###############################################################
#  Generated by:      Cadence Innovus 21.14-s109_1
#  OS:                Linux x86_64(Host ID caen-vnc-mi17.engin.umich.edu)
#  Generated on:      Wed Apr 19 02:55:07 2023
#  Design:            Main_controller
#  Command:           write_lef_abstract /afs/umich.edu/class/eecs627/w23/groups/group4/CNN_LSTM/Main_controller_new/apr/Main_controller/data/Main_controller.lef -specifyTopLayer 4 -stripePin -PGpinLayers 4
###############################################################

VERSION 5.8 ;

BUSBITCHARS "[]" ;
DIVIDERCHAR "/" ;

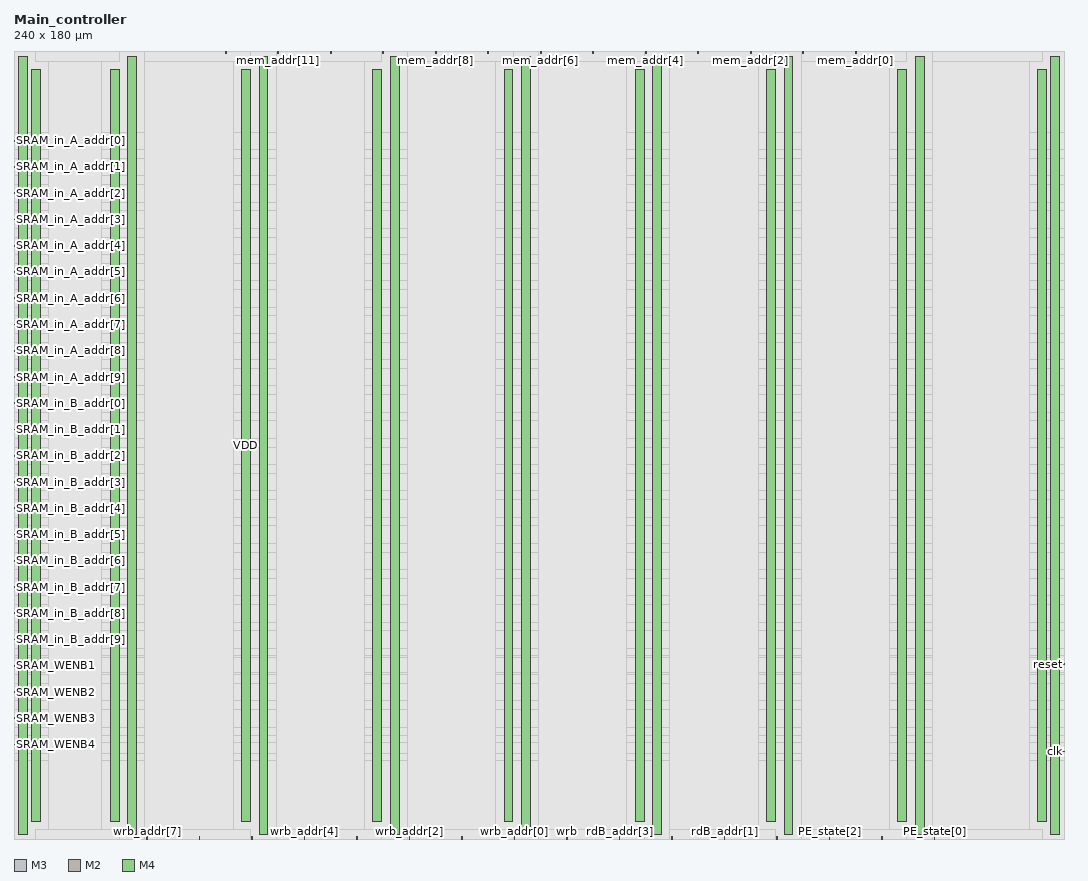
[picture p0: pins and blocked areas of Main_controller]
MACRO Main_controller
  CLASS BLOCK ;
  SIZE 240.000000 BY 180.000000 ;
  FOREIGN Main_controller 0.000000 0.000000 ;
  ORIGIN 0 0 ;
  SYMMETRY X Y R90 ;
  PIN clk
    DIRECTION INPUT ;
    USE SIGNAL ;
    ANTENNAPARTIALMETALAREA 4.3 LAYER M3  ;
    ANTENNAPARTIALMETALSIDEAREA 0.043 LAYER M3  ;
    ANTENNAPARTIALCUTAREA 0.08 LAYER V3  ;
    ANTENNAPARTIALMETALAREA 2.2 LAYER M4  ;
    ANTENNAPARTIALMETALSIDEAREA 0.0224 LAYER M4  ;
    ANTENNAMODEL OXIDE1 ;
    ANTENNAGATEAREA 0.8352 LAYER M4  ;
    ANTENNAMAXAREACAR 3.58046 LAYER M4  ;
    ANTENNAMAXSIDEAREACAR 0.0370929 LAYER M4  ;
    ANTENNAMAXCUTCAR 0.287356 LAYER V4  ;
    PORT
      LAYER M3 ;
        RECT 239.400000 19.900000 240.000000 20.100000 ;
    END
  END clk
  PIN reset
    DIRECTION INPUT ;
    USE SIGNAL ;
    ANTENNAPARTIALMETALAREA 30.9 LAYER M3  ;
    ANTENNAPARTIALMETALSIDEAREA 0.3102 LAYER M3  ;
    ANTENNAMODEL OXIDE1 ;
    ANTENNAGATEAREA 1.1424 LAYER M3  ;
    ANTENNAMAXAREACAR 32.7996 LAYER M3  ;
    ANTENNAMAXSIDEAREACAR 0.329482 LAYER M3  ;
    ANTENNAPARTIALCUTAREA 0.08 LAYER V3  ;
    ANTENNAMAXCUTCAR 1.60849 LAYER V3  ;
    ANTENNAPARTIALMETALAREA 2.44 LAYER M4  ;
    ANTENNAPARTIALMETALSIDEAREA 0.0248 LAYER M4  ;
    ANTENNAGATEAREA 1.2984 LAYER M4  ;
    ANTENNAMAXAREACAR 34.6788 LAYER M4  ;
    ANTENNAMAXSIDEAREACAR 0.348583 LAYER M4  ;
    ANTENNAMAXCUTCAR 1.60849 LAYER V4  ;
    PORT
      LAYER M3 ;
        RECT 239.400000 39.900000 240.000000 40.100000 ;
    END
  END reset
  PIN wrb
    DIRECTION OUTPUT ;
    USE SIGNAL ;
    ANTENNAPARTIALMETALAREA 2.46 LAYER M2  ;
    ANTENNAPARTIALMETALSIDEAREA 0.0246 LAYER M2  ;
    ANTENNAPARTIALCUTAREA 0.08 LAYER V2  ;
    ANTENNADIFFAREA 2.014 LAYER M3  ;
    ANTENNAPARTIALMETALAREA 7.08 LAYER M3  ;
    ANTENNAPARTIALMETALSIDEAREA 0.0712 LAYER M3  ;
    ANTENNAMODEL OXIDE1 ;
    ANTENNAGATEAREA 0.1728 LAYER M3  ;
    ANTENNAMAXAREACAR 81.6696 LAYER M3  ;
    ANTENNAMAXSIDEAREACAR 0.819792 LAYER M3  ;
    ANTENNAMAXCUTCAR 0.925926 LAYER V3  ;
    PORT
      LAYER M2 ;
        RECT 126.300000 0.000000 126.500000 0.600000 ;
    END
  END wrb
  PIN PE_state[2]
    DIRECTION OUTPUT ;
    USE SIGNAL ;
    ANTENNAPARTIALMETALAREA 10.3 LAYER M2  ;
    ANTENNAPARTIALMETALSIDEAREA 0.103 LAYER M2  ;
    ANTENNAPARTIALCUTAREA 0.08 LAYER V2  ;
    ANTENNADIFFAREA 1.792 LAYER M3  ;
    ANTENNAPARTIALMETALAREA 17.08 LAYER M3  ;
    ANTENNAPARTIALMETALSIDEAREA 0.1712 LAYER M3  ;
    PORT
      LAYER M2 ;
        RECT 186.300000 0.000000 186.500000 0.600000 ;
    END
  END PE_state[2]
  PIN PE_state[1]
    DIRECTION OUTPUT ;
    USE SIGNAL ;
    ANTENNAPARTIALMETALAREA 6.7 LAYER M2  ;
    ANTENNAPARTIALMETALSIDEAREA 0.067 LAYER M2  ;
    ANTENNAPARTIALCUTAREA 0.08 LAYER V2  ;
    ANTENNADIFFAREA 1.76 LAYER M3  ;
    ANTENNAPARTIALMETALAREA 14.84 LAYER M3  ;
    ANTENNAPARTIALMETALSIDEAREA 0.1488 LAYER M3  ;
    PORT
      LAYER M2 ;
        RECT 198.300000 0.000000 198.500000 0.600000 ;
    END
  END PE_state[1]
  PIN PE_state[0]
    DIRECTION OUTPUT ;
    USE SIGNAL ;
    ANTENNAPARTIALMETALAREA 9.58 LAYER M2  ;
    ANTENNAPARTIALMETALSIDEAREA 0.0958 LAYER M2  ;
    ANTENNAPARTIALCUTAREA 0.08 LAYER V2  ;
    ANTENNADIFFAREA 1.16 LAYER M3  ;
    ANTENNAPARTIALMETALAREA 17.88 LAYER M3  ;
    ANTENNAPARTIALMETALSIDEAREA 0.1792 LAYER M3  ;
    PORT
      LAYER M2 ;
        RECT 210.300000 0.000000 210.500000 0.600000 ;
    END
  END PE_state[0]
  PIN wrb_addr[7]
    DIRECTION OUTPUT ;
    USE SIGNAL ;
    ANTENNAPARTIALMETALAREA 2.3 LAYER M2  ;
    ANTENNAPARTIALMETALSIDEAREA 0.023 LAYER M2  ;
    ANTENNAPARTIALCUTAREA 0.08 LAYER V2  ;
    ANTENNADIFFAREA 2.014 LAYER M3  ;
    ANTENNAPARTIALMETALAREA 3.96 LAYER M3  ;
    ANTENNAPARTIALMETALSIDEAREA 0.04 LAYER M3  ;
    ANTENNAMODEL OXIDE1 ;
    ANTENNAGATEAREA 0.2808 LAYER M3  ;
    ANTENNAMAXAREACAR 16.9238 LAYER M3  ;
    ANTENNAMAXSIDEAREACAR 0.174117 LAYER M3  ;
    ANTENNAMAXCUTCAR 0.909091 LAYER V3  ;
    PORT
      LAYER M2 ;
        RECT 30.300000 0.000000 30.500000 0.600000 ;
    END
  END wrb_addr[7]
  PIN wrb_addr[6]
    DIRECTION OUTPUT ;
    USE SIGNAL ;
    ANTENNAPARTIALMETALAREA 4.72 LAYER M2  ;
    ANTENNAPARTIALMETALSIDEAREA 0.0472 LAYER M2  ;
    ANTENNAMODEL OXIDE1 ;
    ANTENNAGATEAREA 0.1488 LAYER M2  ;
    ANTENNAMAXAREACAR 33.7184 LAYER M2  ;
    ANTENNAMAXSIDEAREACAR 0.336156 LAYER M2  ;
    ANTENNAPARTIALCUTAREA 0.24 LAYER V2  ;
    ANTENNAMAXCUTCAR 2.15054 LAYER V2  ;
    ANTENNADIFFAREA 2.014 LAYER M3  ;
    ANTENNAPARTIALMETALAREA 4.12 LAYER M3  ;
    ANTENNAPARTIALMETALSIDEAREA 0.0424 LAYER M3  ;
    ANTENNAGATEAREA 0.5688 LAYER M3  ;
    ANTENNAMAXAREACAR 40.9617 LAYER M3  ;
    ANTENNAMAXSIDEAREACAR 0.410699 LAYER M3  ;
    ANTENNAMAXCUTCAR 2.15054 LAYER V3  ;
    PORT
      LAYER M2 ;
        RECT 42.300000 0.000000 42.500000 0.600000 ;
    END
  END wrb_addr[6]
  PIN wrb_addr[5]
    DIRECTION OUTPUT ;
    USE SIGNAL ;
    ANTENNAPARTIALMETALAREA 1.26 LAYER M2  ;
    ANTENNAPARTIALMETALSIDEAREA 0.0126 LAYER M2  ;
    ANTENNAPARTIALCUTAREA 0.08 LAYER V2  ;
    ANTENNADIFFAREA 2.014 LAYER M3  ;
    ANTENNAPARTIALMETALAREA 3.08 LAYER M3  ;
    ANTENNAPARTIALMETALSIDEAREA 0.032 LAYER M3  ;
    ANTENNAMODEL OXIDE1 ;
    ANTENNAGATEAREA 0.528 LAYER M3  ;
    ANTENNAMAXAREACAR 27.5531 LAYER M3  ;
    ANTENNAMAXSIDEAREACAR 0.281036 LAYER M3  ;
    ANTENNAMAXCUTCAR 1.34409 LAYER V3  ;
    PORT
      LAYER M2 ;
        RECT 54.300000 0.000000 54.500000 0.600000 ;
    END
  END wrb_addr[5]
  PIN wrb_addr[4]
    DIRECTION OUTPUT ;
    USE SIGNAL ;
    ANTENNAPARTIALMETALAREA 1.58 LAYER M2  ;
    ANTENNAPARTIALMETALSIDEAREA 0.0158 LAYER M2  ;
    ANTENNAPARTIALCUTAREA 0.08 LAYER V2  ;
    ANTENNADIFFAREA 2.014 LAYER M3  ;
    ANTENNAPARTIALMETALAREA 2.92 LAYER M3  ;
    ANTENNAPARTIALMETALSIDEAREA 0.0304 LAYER M3  ;
    ANTENNAMODEL OXIDE1 ;
    ANTENNAGATEAREA 0.6912 LAYER M3  ;
    ANTENNAMAXAREACAR 7.92454 LAYER M3  ;
    ANTENNAMAXSIDEAREACAR 0.0814174 LAYER M3  ;
    ANTENNAMAXCUTCAR 1.07527 LAYER V3  ;
    PORT
      LAYER M2 ;
        RECT 66.300000 0.000000 66.500000 0.600000 ;
    END
  END wrb_addr[4]
  PIN wrb_addr[3]
    DIRECTION OUTPUT ;
    USE SIGNAL ;
    ANTENNAPARTIALMETALAREA 1.26 LAYER M2  ;
    ANTENNAPARTIALMETALSIDEAREA 0.0126 LAYER M2  ;
    ANTENNAPARTIALCUTAREA 0.08 LAYER V2  ;
    ANTENNADIFFAREA 2.014 LAYER M3  ;
    ANTENNAPARTIALMETALAREA 1.68 LAYER M3  ;
    ANTENNAPARTIALMETALSIDEAREA 0.0176 LAYER M3  ;
    ANTENNAMODEL OXIDE1 ;
    ANTENNAGATEAREA 0.264 LAYER M3  ;
    ANTENNAMAXAREACAR 14.4409 LAYER M3  ;
    ANTENNAMAXSIDEAREACAR 0.146364 LAYER M3  ;
    ANTENNAMAXCUTCAR 0.909091 LAYER V3  ;
    PORT
      LAYER M2 ;
        RECT 78.300000 0.000000 78.500000 0.600000 ;
    END
  END wrb_addr[3]
  PIN wrb_addr[2]
    DIRECTION OUTPUT ;
    USE SIGNAL ;
    ANTENNAPARTIALMETALAREA 1.5 LAYER M2  ;
    ANTENNAPARTIALMETALSIDEAREA 0.015 LAYER M2  ;
    ANTENNAPARTIALCUTAREA 0.08 LAYER V2  ;
    ANTENNADIFFAREA 2.014 LAYER M3  ;
    ANTENNAPARTIALMETALAREA 2.4 LAYER M3  ;
    ANTENNAPARTIALMETALSIDEAREA 0.0248 LAYER M3  ;
    ANTENNAMODEL OXIDE1 ;
    ANTENNAGATEAREA 0.696 LAYER M3  ;
    ANTENNAMAXAREACAR 10.1235 LAYER M3  ;
    ANTENNAMAXSIDEAREACAR 0.101162 LAYER M3  ;
    ANTENNAMAXCUTCAR 0.786164 LAYER V3  ;
    PORT
      LAYER M2 ;
        RECT 90.300000 0.000000 90.500000 0.600000 ;
    END
  END wrb_addr[2]
  PIN wrb_addr[1]
    DIRECTION OUTPUT ;
    USE SIGNAL ;
    ANTENNAPARTIALMETALAREA 1.82 LAYER M2  ;
    ANTENNAPARTIALMETALSIDEAREA 0.0182 LAYER M2  ;
    ANTENNAPARTIALCUTAREA 0.08 LAYER V2  ;
    ANTENNADIFFAREA 2.014 LAYER M3  ;
    ANTENNAPARTIALMETALAREA 5.4 LAYER M3  ;
    ANTENNAPARTIALMETALSIDEAREA 0.0552 LAYER M3  ;
    ANTENNAMODEL OXIDE1 ;
    ANTENNAGATEAREA 0.66 LAYER M3  ;
    ANTENNAMAXAREACAR 13.5468 LAYER M3  ;
    ANTENNAMAXSIDEAREACAR 0.144185 LAYER M3  ;
    ANTENNAMAXCUTCAR 1.78571 LAYER V3  ;
    PORT
      LAYER M2 ;
        RECT 102.300000 0.000000 102.500000 0.600000 ;
    END
  END wrb_addr[1]
  PIN wrb_addr[0]
    DIRECTION OUTPUT ;
    USE SIGNAL ;
    ANTENNAPARTIALMETALAREA 1.82 LAYER M2  ;
    ANTENNAPARTIALMETALSIDEAREA 0.0182 LAYER M2  ;
    ANTENNAPARTIALCUTAREA 0.08 LAYER V2  ;
    ANTENNADIFFAREA 2.014 LAYER M3  ;
    ANTENNAPARTIALMETALAREA 9.8 LAYER M3  ;
    ANTENNAPARTIALMETALSIDEAREA 0.0992 LAYER M3  ;
    ANTENNAMODEL OXIDE1 ;
    ANTENNAGATEAREA 0.4968 LAYER M3  ;
    ANTENNAMAXAREACAR 30.1171 LAYER M3  ;
    ANTENNAMAXSIDEAREACAR 0.312322 LAYER M3  ;
    ANTENNAMAXCUTCAR 1.72414 LAYER V3  ;
    PORT
      LAYER M2 ;
        RECT 114.300000 0.000000 114.500000 0.600000 ;
    END
  END wrb_addr[0]
  PIN rdB_addr[3]
    DIRECTION OUTPUT ;
    USE SIGNAL ;
    ANTENNAPARTIALMETALAREA 3.9 LAYER M2  ;
    ANTENNAPARTIALMETALSIDEAREA 0.039 LAYER M2  ;
    ANTENNAPARTIALCUTAREA 0.08 LAYER V2  ;
    ANTENNADIFFAREA 2.624 LAYER M3  ;
    ANTENNAPARTIALMETALAREA 7.56 LAYER M3  ;
    ANTENNAPARTIALMETALSIDEAREA 0.076 LAYER M3  ;
    PORT
      LAYER M2 ;
        RECT 138.300000 0.000000 138.500000 0.600000 ;
    END
  END rdB_addr[3]
  PIN rdB_addr[2]
    DIRECTION OUTPUT ;
    USE SIGNAL ;
    ANTENNAPARTIALMETALAREA 5.02 LAYER M2  ;
    ANTENNAPARTIALMETALSIDEAREA 0.0502 LAYER M2  ;
    ANTENNAPARTIALCUTAREA 0.08 LAYER V2  ;
    ANTENNADIFFAREA 7.362 LAYER M3  ;
    ANTENNAPARTIALMETALAREA 7.36 LAYER M3  ;
    ANTENNAPARTIALMETALSIDEAREA 0.0744 LAYER M3  ;
    ANTENNAMODEL OXIDE1 ;
    ANTENNAGATEAREA 0.156 LAYER M3  ;
    ANTENNAMAXAREACAR 61.7128 LAYER M3  ;
    ANTENNAMAXSIDEAREACAR 0.625385 LAYER M3  ;
    ANTENNAMAXCUTCAR 0.769231 LAYER V3  ;
    PORT
      LAYER M2 ;
        RECT 150.300000 0.000000 150.500000 0.600000 ;
    END
  END rdB_addr[2]
  PIN rdB_addr[1]
    DIRECTION OUTPUT ;
    USE SIGNAL ;
    ANTENNAPARTIALMETALAREA 8.62 LAYER M2  ;
    ANTENNAPARTIALMETALSIDEAREA 0.0862 LAYER M2  ;
    ANTENNAPARTIALCUTAREA 0.08 LAYER V2  ;
    ANTENNAPARTIALMETALAREA 9.08 LAYER M3  ;
    ANTENNAPARTIALMETALSIDEAREA 0.0912 LAYER M3  ;
    ANTENNAMODEL OXIDE1 ;
    ANTENNAGATEAREA 0.2952 LAYER M3  ;
    ANTENNAMAXAREACAR 32.3686 LAYER M3  ;
    ANTENNAMAXSIDEAREACAR 0.3271 LAYER M3  ;
    ANTENNAPARTIALCUTAREA 0.08 LAYER V3  ;
    ANTENNAMAXCUTCAR 0.677507 LAYER V3  ;
    ANTENNADIFFAREA 7.396 LAYER M4  ;
    ANTENNAPARTIALMETALAREA 3.88 LAYER M4  ;
    ANTENNAPARTIALMETALSIDEAREA 0.0392 LAYER M4  ;
    ANTENNAGATEAREA 0.468 LAYER M4  ;
    ANTENNAMAXAREACAR 40.6592 LAYER M4  ;
    ANTENNAMAXSIDEAREACAR 0.410861 LAYER M4  ;
    ANTENNAMAXCUTCAR 1.15741 LAYER V4  ;
    PORT
      LAYER M2 ;
        RECT 162.300000 0.000000 162.500000 0.600000 ;
    END
  END rdB_addr[1]
  PIN rdB_addr[0]
    DIRECTION OUTPUT ;
    USE SIGNAL ;
    ANTENNAPARTIALMETALAREA 8.94 LAYER M2  ;
    ANTENNAPARTIALMETALSIDEAREA 0.0894 LAYER M2  ;
    ANTENNAPARTIALCUTAREA 0.08 LAYER V2  ;
    ANTENNADIFFAREA 3.348 LAYER M3  ;
    ANTENNAPARTIALMETALAREA 12.08 LAYER M3  ;
    ANTENNAPARTIALMETALSIDEAREA 0.1216 LAYER M3  ;
    ANTENNAMODEL OXIDE1 ;
    ANTENNAGATEAREA 0.624 LAYER M3  ;
    ANTENNAMAXAREACAR 32.1275 LAYER M3  ;
    ANTENNAMAXSIDEAREACAR 0.320335 LAYER M3  ;
    ANTENNAMAXCUTCAR 0.925926 LAYER V3  ;
    PORT
      LAYER M2 ;
        RECT 174.300000 0.000000 174.500000 0.600000 ;
    END
  END rdB_addr[0]
  PIN mem_addr[12]
    DIRECTION OUTPUT ;
    USE SIGNAL ;
    ANTENNAPARTIALMETALAREA 1.5944 LAYER M2  ;
    ANTENNAPARTIALMETALSIDEAREA 0.01596 LAYER M2  ;
    ANTENNAPARTIALCUTAREA 0.08 LAYER V2  ;
    ANTENNADIFFAREA 2.014 LAYER M3  ;
    ANTENNAPARTIALMETALAREA 2.4 LAYER M3  ;
    ANTENNAPARTIALMETALSIDEAREA 0.0248 LAYER M3  ;
    ANTENNAMODEL OXIDE1 ;
    ANTENNAGATEAREA 0.2904 LAYER M3  ;
    ANTENNAMAXAREACAR 29.2675 LAYER M3  ;
    ANTENNAMAXSIDEAREACAR 0.298884 LAYER M3  ;
    ANTENNAMAXCUTCAR 1.51515 LAYER V3  ;
    PORT
      LAYER M2 ;
        RECT 48.320000 179.440000 48.480000 180.000000 ;
    END
  END mem_addr[12]
  PIN mem_addr[11]
    DIRECTION OUTPUT ;
    USE SIGNAL ;
    ANTENNAPARTIALMETALAREA 1.7544 LAYER M2  ;
    ANTENNAPARTIALMETALSIDEAREA 0.01756 LAYER M2  ;
    ANTENNAPARTIALCUTAREA 0.08 LAYER V2  ;
    ANTENNADIFFAREA 2.014 LAYER M3  ;
    ANTENNAPARTIALMETALAREA 0.84 LAYER M3  ;
    ANTENNAPARTIALMETALSIDEAREA 0.0088 LAYER M3  ;
    ANTENNAMODEL OXIDE1 ;
    ANTENNAGATEAREA 0.372 LAYER M3  ;
    ANTENNAMAXAREACAR 11.4153 LAYER M3  ;
    ANTENNAMAXSIDEAREACAR 0.118732 LAYER M3  ;
    ANTENNAMAXCUTCAR 0.757576 LAYER V3  ;
    PORT
      LAYER M2 ;
        RECT 60.320000 179.440000 60.480000 180.000000 ;
    END
  END mem_addr[11]
  PIN mem_addr[10]
    DIRECTION OUTPUT ;
    USE SIGNAL ;
    ANTENNAPARTIALMETALAREA 2.164 LAYER M2  ;
    ANTENNAPARTIALMETALSIDEAREA 0.02164 LAYER M2  ;
    ANTENNAMODEL OXIDE1 ;
    ANTENNAGATEAREA 0.1176 LAYER M2  ;
    ANTENNAMAXAREACAR 19.8707 LAYER M2  ;
    ANTENNAMAXSIDEAREACAR 0.20034 LAYER M2  ;
    ANTENNAPARTIALCUTAREA 0.08 LAYER V2  ;
    ANTENNAMAXCUTCAR 1.02041 LAYER V2  ;
    ANTENNADIFFAREA 2.014 LAYER M3  ;
    ANTENNAPARTIALMETALAREA 1.24 LAYER M3  ;
    ANTENNAPARTIALMETALSIDEAREA 0.0128 LAYER M3  ;
    ANTENNAGATEAREA 0.4896 LAYER M3  ;
    ANTENNAMAXAREACAR 22.4034 LAYER M3  ;
    ANTENNAMAXSIDEAREACAR 0.226484 LAYER M3  ;
    ANTENNAMAXCUTCAR 1.02041 LAYER V3  ;
    PORT
      LAYER M2 ;
        RECT 72.320000 179.440000 72.480000 180.000000 ;
    END
  END mem_addr[10]
  PIN mem_addr[9]
    DIRECTION OUTPUT ;
    USE SIGNAL ;
    ANTENNAPARTIALMETALAREA 1.4344 LAYER M2  ;
    ANTENNAPARTIALMETALSIDEAREA 0.01436 LAYER M2  ;
    ANTENNAPARTIALCUTAREA 0.08 LAYER V2  ;
    ANTENNADIFFAREA 2.014 LAYER M3  ;
    ANTENNAPARTIALMETALAREA 1.28 LAYER M3  ;
    ANTENNAPARTIALMETALSIDEAREA 0.0136 LAYER M3  ;
    ANTENNAMODEL OXIDE1 ;
    ANTENNAGATEAREA 0.408 LAYER M3  ;
    ANTENNAMAXAREACAR 16.2988 LAYER M3  ;
    ANTENNAMAXSIDEAREACAR 0.165492 LAYER M3  ;
    ANTENNAMAXCUTCAR 1.16657 LAYER V3  ;
    PORT
      LAYER M2 ;
        RECT 84.320000 179.440000 84.480000 180.000000 ;
    END
  END mem_addr[9]
  PIN mem_addr[8]
    DIRECTION OUTPUT ;
    USE SIGNAL ;
    ANTENNAPARTIALMETALAREA 1.9944 LAYER M2  ;
    ANTENNAPARTIALMETALSIDEAREA 0.01996 LAYER M2  ;
    ANTENNAPARTIALCUTAREA 0.08 LAYER V2  ;
    ANTENNADIFFAREA 2.014 LAYER M3  ;
    ANTENNAPARTIALMETALAREA 1.24 LAYER M3  ;
    ANTENNAPARTIALMETALSIDEAREA 0.0128 LAYER M3  ;
    ANTENNAMODEL OXIDE1 ;
    ANTENNAGATEAREA 0.4896 LAYER M3  ;
    ANTENNAMAXAREACAR 10.8861 LAYER M3  ;
    ANTENNAMAXSIDEAREACAR 0.112519 LAYER M3  ;
    ANTENNAMAXCUTCAR 0.757576 LAYER V3  ;
    PORT
      LAYER M2 ;
        RECT 96.320000 179.440000 96.480000 180.000000 ;
    END
  END mem_addr[8]
  PIN mem_addr[7]
    DIRECTION OUTPUT ;
    USE SIGNAL ;
    ANTENNAPARTIALMETALAREA 1.9144 LAYER M2  ;
    ANTENNAPARTIALMETALSIDEAREA 0.01916 LAYER M2  ;
    ANTENNAPARTIALCUTAREA 0.08 LAYER V2  ;
    ANTENNADIFFAREA 2.014 LAYER M3  ;
    ANTENNAPARTIALMETALAREA 3.4 LAYER M3  ;
    ANTENNAPARTIALMETALSIDEAREA 0.0344 LAYER M3  ;
    ANTENNAMODEL OXIDE1 ;
    ANTENNAGATEAREA 0.4896 LAYER M3  ;
    ANTENNAMAXAREACAR 11.5562 LAYER M3  ;
    ANTENNAMAXSIDEAREACAR 0.119883 LAYER M3  ;
    ANTENNAMAXCUTCAR 1.02041 LAYER V3  ;
    PORT
      LAYER M2 ;
        RECT 108.320000 179.440000 108.480000 180.000000 ;
    END
  END mem_addr[7]
  PIN mem_addr[6]
    DIRECTION OUTPUT ;
    USE SIGNAL ;
    ANTENNAPARTIALMETALAREA 1.9944 LAYER M2  ;
    ANTENNAPARTIALMETALSIDEAREA 0.01996 LAYER M2  ;
    ANTENNAMODEL OXIDE1 ;
    ANTENNAGATEAREA 0.1536 LAYER M2  ;
    ANTENNAMAXAREACAR 14.3034 LAYER M2  ;
    ANTENNAMAXSIDEAREACAR 0.14388 LAYER M2  ;
    ANTENNAPARTIALCUTAREA 0.08 LAYER V2  ;
    ANTENNAMAXCUTCAR 0.78125 LAYER V2  ;
    ANTENNADIFFAREA 2.014 LAYER M3  ;
    ANTENNAPARTIALMETALAREA 3.04 LAYER M3  ;
    ANTENNAPARTIALMETALSIDEAREA 0.0312 LAYER M3  ;
    ANTENNAGATEAREA 0.516 LAYER M3  ;
    ANTENNAMAXAREACAR 20.1949 LAYER M3  ;
    ANTENNAMAXSIDEAREACAR 0.204345 LAYER M3  ;
    ANTENNAMAXCUTCAR 1.6129 LAYER V3  ;
    PORT
      LAYER M2 ;
        RECT 120.320000 179.440000 120.480000 180.000000 ;
    END
  END mem_addr[6]
  PIN mem_addr[5]
    DIRECTION OUTPUT ;
    USE SIGNAL ;
    ANTENNADIFFAREA 2.014 LAYER M2  ;
    ANTENNAPARTIALMETALAREA 4.0744 LAYER M2  ;
    ANTENNAPARTIALMETALSIDEAREA 0.04076 LAYER M2  ;
    ANTENNAPARTIALCUTAREA 0.08 LAYER V2  ;
    ANTENNADIFFAREA 2.014 LAYER M3  ;
    ANTENNAPARTIALMETALAREA 0.84 LAYER M3  ;
    ANTENNAPARTIALMETALSIDEAREA 0.0088 LAYER M3  ;
    ANTENNAMODEL OXIDE1 ;
    ANTENNAGATEAREA 0.4896 LAYER M3  ;
    ANTENNAMAXAREACAR 5.47976 LAYER M3  ;
    ANTENNAMAXSIDEAREACAR 0.058455 LAYER M3  ;
    ANTENNAMAXCUTCAR 0.757576 LAYER V3  ;
    PORT
      LAYER M2 ;
        RECT 132.320000 179.440000 132.480000 180.000000 ;
    END
  END mem_addr[5]
  PIN mem_addr[4]
    DIRECTION OUTPUT ;
    USE SIGNAL ;
    ANTENNAPARTIALMETALAREA 1.9144 LAYER M2  ;
    ANTENNAPARTIALMETALSIDEAREA 0.01916 LAYER M2  ;
    ANTENNAPARTIALCUTAREA 0.08 LAYER V2  ;
    ANTENNADIFFAREA 2.014 LAYER M3  ;
    ANTENNAPARTIALMETALAREA 3.76 LAYER M3  ;
    ANTENNAPARTIALMETALSIDEAREA 0.0384 LAYER M3  ;
    ANTENNAMODEL OXIDE1 ;
    ANTENNAGATEAREA 0.4896 LAYER M3  ;
    ANTENNAMAXAREACAR 11.3436 LAYER M3  ;
    ANTENNAMAXSIDEAREACAR 0.118225 LAYER M3  ;
    ANTENNAMAXCUTCAR 1.02041 LAYER V3  ;
    PORT
      LAYER M2 ;
        RECT 144.320000 179.440000 144.480000 180.000000 ;
    END
  END mem_addr[4]
  PIN mem_addr[3]
    DIRECTION OUTPUT ;
    USE SIGNAL ;
    ANTENNAPARTIALMETALAREA 1.9144 LAYER M2  ;
    ANTENNAPARTIALMETALSIDEAREA 0.01916 LAYER M2  ;
    ANTENNAPARTIALCUTAREA 0.08 LAYER V2  ;
    ANTENNADIFFAREA 2.014 LAYER M3  ;
    ANTENNAPARTIALMETALAREA 4.72 LAYER M3  ;
    ANTENNAPARTIALMETALSIDEAREA 0.048 LAYER M3  ;
    ANTENNAMODEL OXIDE1 ;
    ANTENNAGATEAREA 0.4776 LAYER M3  ;
    ANTENNAMAXAREACAR 24.0781 LAYER M3  ;
    ANTENNAMAXSIDEAREACAR 0.244027 LAYER M3  ;
    ANTENNAMAXCUTCAR 1.59387 LAYER V3  ;
    PORT
      LAYER M2 ;
        RECT 156.320000 179.440000 156.480000 180.000000 ;
    END
  END mem_addr[3]
  PIN mem_addr[2]
    DIRECTION OUTPUT ;
    USE SIGNAL ;
    ANTENNAPARTIALMETALAREA 2.3144 LAYER M2  ;
    ANTENNAPARTIALMETALSIDEAREA 0.02316 LAYER M2  ;
    ANTENNAPARTIALCUTAREA 0.08 LAYER V2  ;
    ANTENNADIFFAREA 2.014 LAYER M3  ;
    ANTENNAPARTIALMETALAREA 5 LAYER M3  ;
    ANTENNAPARTIALMETALSIDEAREA 0.0504 LAYER M3  ;
    ANTENNAMODEL OXIDE1 ;
    ANTENNAGATEAREA 0.372 LAYER M3  ;
    ANTENNAMAXAREACAR 15.5274 LAYER M3  ;
    ANTENNAMAXSIDEAREACAR 0.159853 LAYER M3  ;
    ANTENNAPARTIALCUTAREA 0.08 LAYER V3  ;
    ANTENNAMAXCUTCAR 0.97263 LAYER V3  ;
    ANTENNADIFFAREA 2.014 LAYER M4  ;
    ANTENNAPARTIALMETALAREA 0.6 LAYER M4  ;
    ANTENNAPARTIALMETALSIDEAREA 0.0064 LAYER M4  ;
    ANTENNAGATEAREA 0.4896 LAYER M4  ;
    ANTENNAMAXAREACAR 16.7528 LAYER M4  ;
    ANTENNAMAXSIDEAREACAR 0.172924 LAYER M4  ;
    ANTENNAMAXCUTCAR 1.70068 LAYER V4  ;
    PORT
      LAYER M2 ;
        RECT 168.320000 179.440000 168.480000 180.000000 ;
    END
  END mem_addr[2]
  PIN mem_addr[1]
    DIRECTION OUTPUT ;
    USE SIGNAL ;
    ANTENNAPARTIALMETALAREA 3.5144 LAYER M2  ;
    ANTENNAPARTIALMETALSIDEAREA 0.03516 LAYER M2  ;
    ANTENNAPARTIALCUTAREA 0.08 LAYER V2  ;
    ANTENNADIFFAREA 2.014 LAYER M3  ;
    ANTENNAPARTIALMETALAREA 3.96 LAYER M3  ;
    ANTENNAPARTIALMETALSIDEAREA 0.04 LAYER M3  ;
    ANTENNAMODEL OXIDE1 ;
    ANTENNAGATEAREA 0.2976 LAYER M3  ;
    ANTENNAMAXAREACAR 22.4445 LAYER M3  ;
    ANTENNAMAXSIDEAREACAR 0.235221 LAYER M3  ;
    ANTENNAMAXCUTCAR 1.41824 LAYER V3  ;
    PORT
      LAYER M2 ;
        RECT 180.320000 179.440000 180.480000 180.000000 ;
    END
  END mem_addr[1]
  PIN mem_addr[0]
    DIRECTION OUTPUT ;
    USE SIGNAL ;
    ANTENNAPARTIALMETALAREA 3.0344 LAYER M2  ;
    ANTENNAPARTIALMETALSIDEAREA 0.03036 LAYER M2  ;
    ANTENNAPARTIALCUTAREA 0.08 LAYER V2  ;
    ANTENNADIFFAREA 2.014 LAYER M3  ;
    ANTENNAPARTIALMETALAREA 6.28 LAYER M3  ;
    ANTENNAPARTIALMETALSIDEAREA 0.0632 LAYER M3  ;
    ANTENNAMODEL OXIDE1 ;
    ANTENNAGATEAREA 0.3048 LAYER M3  ;
    ANTENNAMAXAREACAR 23.7103 LAYER M3  ;
    ANTENNAMAXSIDEAREACAR 0.241249 LAYER M3  ;
    ANTENNAMAXCUTCAR 0.540245 LAYER V3  ;
    PORT
      LAYER M2 ;
        RECT 192.320000 179.440000 192.480000 180.000000 ;
    END
  END mem_addr[0]
  PIN SRAM_in_A_addr[9]
    DIRECTION OUTPUT ;
    USE SIGNAL ;
    ANTENNAPARTIALMETALAREA 11.1544 LAYER M3  ;
    ANTENNAPARTIALMETALSIDEAREA 0.11196 LAYER M3  ;
    ANTENNAPARTIALCUTAREA 0.08 LAYER V3  ;
    ANTENNADIFFAREA 2.176 LAYER M4  ;
    ANTENNAPARTIALMETALAREA 4.68 LAYER M4  ;
    ANTENNAPARTIALMETALSIDEAREA 0.0472 LAYER M4  ;
    ANTENNAMODEL OXIDE1 ;
    ANTENNAGATEAREA 0.7344 LAYER M4  ;
    ANTENNAMAXAREACAR 27.4867 LAYER M4  ;
    ANTENNAMAXSIDEAREACAR 0.277922 LAYER M4  ;
    ANTENNAMAXCUTCAR 1.24534 LAYER V4  ;
    PORT
      LAYER M3 ;
        RECT 0.000000 105.520000 0.560000 105.680000 ;
    END
  END SRAM_in_A_addr[9]
  PIN SRAM_in_A_addr[8]
    DIRECTION OUTPUT ;
    USE SIGNAL ;
    ANTENNAPARTIALMETALAREA 5.9144 LAYER M3  ;
    ANTENNAPARTIALMETALSIDEAREA 0.05916 LAYER M3  ;
    ANTENNAPARTIALCUTAREA 0.08 LAYER V3  ;
    ANTENNADIFFAREA 4.168 LAYER M4  ;
    ANTENNAPARTIALMETALAREA 6.08 LAYER M4  ;
    ANTENNAPARTIALMETALSIDEAREA 0.0616 LAYER M4  ;
    ANTENNAMODEL OXIDE1 ;
    ANTENNAGATEAREA 1.1496 LAYER M4  ;
    ANTENNAMAXAREACAR 20.409 LAYER M4  ;
    ANTENNAMAXSIDEAREACAR 0.213352 LAYER M4  ;
    ANTENNAMAXCUTCAR 1.07576 LAYER V4  ;
    PORT
      LAYER M3 ;
        RECT 0.000000 111.520000 0.560000 111.680000 ;
    END
  END SRAM_in_A_addr[8]
  PIN SRAM_in_A_addr[7]
    DIRECTION OUTPUT ;
    USE SIGNAL ;
    ANTENNADIFFAREA 4.168 LAYER M3  ;
    ANTENNAPARTIALMETALAREA 16.804 LAYER M3  ;
    ANTENNAPARTIALMETALSIDEAREA 0.16964 LAYER M3  ;
    ANTENNAMODEL OXIDE1 ;
    ANTENNAGATEAREA 0.9312 LAYER M3  ;
    ANTENNAMAXAREACAR 33.0733 LAYER M3  ;
    ANTENNAMAXSIDEAREACAR 0.344674 LAYER M3  ;
    ANTENNAPARTIALCUTAREA 0.08 LAYER V3  ;
    ANTENNAMAXCUTCAR 2.16924 LAYER V3  ;
    ANTENNADIFFAREA 4.168 LAYER M4  ;
    ANTENNAPARTIALMETALAREA 2.36 LAYER M4  ;
    ANTENNAPARTIALMETALSIDEAREA 0.024 LAYER M4  ;
    ANTENNAGATEAREA 1.0896 LAYER M4  ;
    ANTENNAMAXAREACAR 35.2392 LAYER M4  ;
    ANTENNAMAXSIDEAREACAR 0.3667 LAYER M4  ;
    ANTENNAMAXCUTCAR 2.16924 LAYER V4  ;
    PORT
      LAYER M3 ;
        RECT 0.000000 117.520000 0.560000 117.680000 ;
    END
  END SRAM_in_A_addr[7]
  PIN SRAM_in_A_addr[6]
    DIRECTION OUTPUT ;
    USE SIGNAL ;
    ANTENNADIFFAREA 4.168 LAYER M3  ;
    ANTENNAPARTIALMETALAREA 20.6344 LAYER M3  ;
    ANTENNAPARTIALMETALSIDEAREA 0.20876 LAYER M3  ;
    ANTENNAMODEL OXIDE1 ;
    ANTENNAGATEAREA 3.2544 LAYER M3  ;
    ANTENNAMAXAREACAR 51.8503 LAYER M3  ;
    ANTENNAMAXSIDEAREACAR 0.523461 LAYER M3  ;
    ANTENNAMAXCUTCAR 1.6129 LAYER V3  ;
    PORT
      LAYER M3 ;
        RECT 0.000000 123.520000 0.560000 123.680000 ;
    END
  END SRAM_in_A_addr[6]
  PIN SRAM_in_A_addr[5]
    DIRECTION OUTPUT ;
    USE SIGNAL ;
    ANTENNAPARTIALMETALAREA 9.9144 LAYER M3  ;
    ANTENNAPARTIALMETALSIDEAREA 0.09996 LAYER M3  ;
    ANTENNAMODEL OXIDE1 ;
    ANTENNAGATEAREA 0.444 LAYER M3  ;
    ANTENNAMAXAREACAR 36.3831 LAYER M3  ;
    ANTENNAMAXSIDEAREACAR 0.365455 LAYER M3  ;
    ANTENNAPARTIALCUTAREA 0.08 LAYER V3  ;
    ANTENNAMAXCUTCAR 1.25545 LAYER V3  ;
    ANTENNADIFFAREA 3.996 LAYER M4  ;
    ANTENNAPARTIALMETALAREA 9.16 LAYER M4  ;
    ANTENNAPARTIALMETALSIDEAREA 0.0928 LAYER M4  ;
    ANTENNAGATEAREA 2.532 LAYER M4  ;
    ANTENNAMAXAREACAR 40.0007 LAYER M4  ;
    ANTENNAMAXSIDEAREACAR 0.402106 LAYER M4  ;
    ANTENNAMAXCUTCAR 1.77175 LAYER V4  ;
    PORT
      LAYER M3 ;
        RECT 0.000000 129.520000 0.560000 129.680000 ;
    END
  END SRAM_in_A_addr[5]
  PIN SRAM_in_A_addr[4]
    DIRECTION OUTPUT ;
    USE SIGNAL ;
    ANTENNADIFFAREA 2.014 LAYER M3  ;
    ANTENNAPARTIALMETALAREA 12.5144 LAYER M3  ;
    ANTENNAPARTIALMETALSIDEAREA 0.12556 LAYER M3  ;
    ANTENNAMODEL OXIDE1 ;
    ANTENNAGATEAREA 0.372 LAYER M3  ;
    ANTENNAMAXAREACAR 46.8385 LAYER M3  ;
    ANTENNAMAXSIDEAREACAR 0.473007 LAYER M3  ;
    ANTENNAMAXCUTCAR 0.757576 LAYER V3  ;
    PORT
      LAYER M3 ;
        RECT 0.000000 135.520000 0.560000 135.680000 ;
    END
  END SRAM_in_A_addr[4]
  PIN SRAM_in_A_addr[3]
    DIRECTION OUTPUT ;
    USE SIGNAL ;
    ANTENNADIFFAREA 4.168 LAYER M3  ;
    ANTENNAPARTIALMETALAREA 13.7944 LAYER M3  ;
    ANTENNAPARTIALMETALSIDEAREA 0.13916 LAYER M3  ;
    ANTENNAMODEL OXIDE1 ;
    ANTENNAGATEAREA 1.2768 LAYER M3  ;
    ANTENNAMAXAREACAR 41.9073 LAYER M3  ;
    ANTENNAMAXSIDEAREACAR 0.426924 LAYER M3  ;
    ANTENNAMAXCUTCAR 1.47679 LAYER V3  ;
    PORT
      LAYER M3 ;
        RECT 0.000000 141.520000 0.560000 141.680000 ;
    END
  END SRAM_in_A_addr[3]
  PIN SRAM_in_A_addr[2]
    DIRECTION OUTPUT ;
    USE SIGNAL ;
    ANTENNADIFFAREA 4.168 LAYER M3  ;
    ANTENNAPARTIALMETALAREA 13.4744 LAYER M3  ;
    ANTENNAPARTIALMETALSIDEAREA 0.13596 LAYER M3  ;
    ANTENNAMODEL OXIDE1 ;
    ANTENNAGATEAREA 0.792 LAYER M3  ;
    ANTENNAMAXAREACAR 20.6759 LAYER M3  ;
    ANTENNAMAXSIDEAREACAR 0.211641 LAYER M3  ;
    ANTENNAPARTIALCUTAREA 0.16 LAYER V3  ;
    ANTENNAMAXCUTCAR 1.5041 LAYER V3  ;
    ANTENNADIFFAREA 4.168 LAYER M4  ;
    ANTENNAPARTIALMETALAREA 12.84 LAYER M4  ;
    ANTENNAPARTIALMETALSIDEAREA 0.1296 LAYER M4  ;
    ANTENNAGATEAREA 1.4832 LAYER M4  ;
    ANTENNAMAXAREACAR 29.3328 LAYER M4  ;
    ANTENNAMAXSIDEAREACAR 0.299019 LAYER M4  ;
    ANTENNAMAXCUTCAR 2.87356 LAYER V4  ;
    PORT
      LAYER M3 ;
        RECT 0.000000 147.520000 0.560000 147.680000 ;
    END
  END SRAM_in_A_addr[2]
  PIN SRAM_in_A_addr[1]
    DIRECTION OUTPUT ;
    USE SIGNAL ;
    ANTENNADIFFAREA 4.168 LAYER M3  ;
    ANTENNAPARTIALMETALAREA 15.5544 LAYER M3  ;
    ANTENNAPARTIALMETALSIDEAREA 0.15676 LAYER M3  ;
    ANTENNAMODEL OXIDE1 ;
    ANTENNAGATEAREA 1.8432 LAYER M3  ;
    ANTENNAMAXAREACAR 42.5837 LAYER M3  ;
    ANTENNAMAXSIDEAREACAR 0.432829 LAYER M3  ;
    ANTENNAMAXCUTCAR 1.192 LAYER V3  ;
    PORT
      LAYER M3 ;
        RECT 0.000000 153.520000 0.560000 153.680000 ;
    END
  END SRAM_in_A_addr[1]
  PIN SRAM_in_A_addr[0]
    DIRECTION OUTPUT ;
    USE SIGNAL ;
    ANTENNAPARTIALMETALAREA 7.5144 LAYER M3  ;
    ANTENNAPARTIALMETALSIDEAREA 0.07516 LAYER M3  ;
    ANTENNAPARTIALCUTAREA 0.08 LAYER V3  ;
    ANTENNADIFFAREA 2.176 LAYER M4  ;
    ANTENNAPARTIALMETALAREA 9.56 LAYER M4  ;
    ANTENNAPARTIALMETALSIDEAREA 0.096 LAYER M4  ;
    ANTENNAMODEL OXIDE1 ;
    ANTENNAGATEAREA 1.0152 LAYER M4  ;
    ANTENNAMAXAREACAR 45.2025 LAYER M4  ;
    ANTENNAMAXSIDEAREACAR 0.454717 LAYER M4  ;
    ANTENNAMAXCUTCAR 1.82394 LAYER V4  ;
    PORT
      LAYER M3 ;
        RECT 0.000000 159.520000 0.560000 159.680000 ;
    END
  END SRAM_in_A_addr[0]
  PIN SRAM_in_B_addr[9]
    DIRECTION OUTPUT ;
    USE SIGNAL ;
    ANTENNAPARTIALMETALAREA 1.7544 LAYER M3  ;
    ANTENNAPARTIALMETALSIDEAREA 0.01756 LAYER M3  ;
    ANTENNAPARTIALCUTAREA 0.08 LAYER V3  ;
    ANTENNADIFFAREA 2.014 LAYER M4  ;
    ANTENNAPARTIALMETALAREA 3.2 LAYER M4  ;
    ANTENNAPARTIALMETALSIDEAREA 0.0328 LAYER M4  ;
    ANTENNAMODEL OXIDE1 ;
    ANTENNAGATEAREA 0.54 LAYER M4  ;
    ANTENNAMAXAREACAR 31.6148 LAYER M4  ;
    ANTENNAMAXSIDEAREACAR 0.327963 LAYER M4  ;
    ANTENNAMAXCUTCAR 2.77778 LAYER V4  ;
    PORT
      LAYER M3 ;
        RECT 0.000000 45.520000 0.560000 45.680000 ;
    END
  END SRAM_in_B_addr[9]
  PIN SRAM_in_B_addr[8]
    DIRECTION OUTPUT ;
    USE SIGNAL ;
    ANTENNAPARTIALMETALAREA 5.8744 LAYER M3  ;
    ANTENNAPARTIALMETALSIDEAREA 0.05916 LAYER M3  ;
    ANTENNAMODEL OXIDE1 ;
    ANTENNAGATEAREA 0.2856 LAYER M3  ;
    ANTENNAMAXAREACAR 31.3131 LAYER M3  ;
    ANTENNAMAXSIDEAREACAR 0.324365 LAYER M3  ;
    ANTENNAPARTIALCUTAREA 0.08 LAYER V3  ;
    ANTENNAMAXCUTCAR 1.94678 LAYER V3  ;
    ANTENNADIFFAREA 2.014 LAYER M4  ;
    ANTENNAPARTIALMETALAREA 3 LAYER M4  ;
    ANTENNAPARTIALMETALSIDEAREA 0.0304 LAYER M4  ;
    ANTENNAGATEAREA 0.3576 LAYER M4  ;
    ANTENNAMAXAREACAR 51.8559 LAYER M4  ;
    ANTENNAMAXSIDEAREACAR 0.530011 LAYER M4  ;
    ANTENNAMAXCUTCAR 2.77778 LAYER V4  ;
    PORT
      LAYER M3 ;
        RECT 0.000000 51.520000 0.560000 51.680000 ;
    END
  END SRAM_in_B_addr[8]
  PIN SRAM_in_B_addr[7]
    DIRECTION OUTPUT ;
    USE SIGNAL ;
    ANTENNADIFFAREA 2.014 LAYER M3  ;
    ANTENNAPARTIALMETALAREA 3.7144 LAYER M3  ;
    ANTENNAPARTIALMETALSIDEAREA 0.03756 LAYER M3  ;
    ANTENNAMODEL OXIDE1 ;
    ANTENNAGATEAREA 0.6312 LAYER M3  ;
    ANTENNAMAXAREACAR 17.9665 LAYER M3  ;
    ANTENNAMAXSIDEAREACAR 0.179596 LAYER M3  ;
    ANTENNAMAXCUTCAR 1.21212 LAYER V3  ;
    PORT
      LAYER M3 ;
        RECT 0.000000 57.520000 0.560000 57.680000 ;
    END
  END SRAM_in_B_addr[7]
  PIN SRAM_in_B_addr[6]
    DIRECTION OUTPUT ;
    USE SIGNAL ;
    ANTENNADIFFAREA 2.014 LAYER M3  ;
    ANTENNAPARTIALMETALAREA 8.8344 LAYER M3  ;
    ANTENNAPARTIALMETALSIDEAREA 0.08956 LAYER M3  ;
    ANTENNAMODEL OXIDE1 ;
    ANTENNAGATEAREA 0.5712 LAYER M3  ;
    ANTENNAMAXAREACAR 36.8651 LAYER M3  ;
    ANTENNAMAXSIDEAREACAR 0.377679 LAYER M3  ;
    ANTENNAMAXCUTCAR 1.92308 LAYER V3  ;
    PORT
      LAYER M3 ;
        RECT 0.000000 63.520000 0.560000 63.680000 ;
    END
  END SRAM_in_B_addr[6]
  PIN SRAM_in_B_addr[5]
    DIRECTION OUTPUT ;
    USE SIGNAL ;
    ANTENNADIFFAREA 2.014 LAYER M3  ;
    ANTENNAPARTIALMETALAREA 7.7144 LAYER M3  ;
    ANTENNAPARTIALMETALSIDEAREA 0.07836 LAYER M3  ;
    ANTENNAMODEL OXIDE1 ;
    ANTENNAGATEAREA 0.8448 LAYER M3  ;
    ANTENNAMAXAREACAR 27.7104 LAYER M3  ;
    ANTENNAMAXSIDEAREACAR 0.281998 LAYER M3  ;
    ANTENNAMAXCUTCAR 1.6129 LAYER V3  ;
    PORT
      LAYER M3 ;
        RECT 0.000000 69.520000 0.560000 69.680000 ;
    END
  END SRAM_in_B_addr[5]
  PIN SRAM_in_B_addr[4]
    DIRECTION OUTPUT ;
    USE SIGNAL ;
    ANTENNADIFFAREA 2.014 LAYER M3  ;
    ANTENNAPARTIALMETALAREA 5.0344 LAYER M3  ;
    ANTENNAPARTIALMETALSIDEAREA 0.05036 LAYER M3  ;
    ANTENNAMODEL OXIDE1 ;
    ANTENNAGATEAREA 0.5088 LAYER M3  ;
    ANTENNAMAXAREACAR 19.3825 LAYER M3  ;
    ANTENNAMAXSIDEAREACAR 0.197311 LAYER M3  ;
    ANTENNAMAXCUTCAR 0.917874 LAYER V3  ;
    PORT
      LAYER M3 ;
        RECT 0.000000 75.520000 0.560000 75.680000 ;
    END
  END SRAM_in_B_addr[4]
  PIN SRAM_in_B_addr[3]
    DIRECTION OUTPUT ;
    USE SIGNAL ;
    ANTENNADIFFAREA 2.014 LAYER M3  ;
    ANTENNAPARTIALMETALAREA 7.1144 LAYER M3  ;
    ANTENNAPARTIALMETALSIDEAREA 0.07196 LAYER M3  ;
    ANTENNAMODEL OXIDE1 ;
    ANTENNAGATEAREA 0.5424 LAYER M3  ;
    ANTENNAMAXAREACAR 25.2484 LAYER M3  ;
    ANTENNAMAXSIDEAREACAR 0.254022 LAYER M3  ;
    ANTENNAMAXCUTCAR 1.83575 LAYER V3  ;
    PORT
      LAYER M3 ;
        RECT 0.000000 81.520000 0.560000 81.680000 ;
    END
  END SRAM_in_B_addr[3]
  PIN SRAM_in_B_addr[2]
    DIRECTION OUTPUT ;
    USE SIGNAL ;
    ANTENNADIFFAREA 2.014 LAYER M3  ;
    ANTENNAPARTIALMETALAREA 4.8744 LAYER M3  ;
    ANTENNAPARTIALMETALSIDEAREA 0.04956 LAYER M3  ;
    ANTENNAMODEL OXIDE1 ;
    ANTENNAGATEAREA 0.42 LAYER M3  ;
    ANTENNAMAXAREACAR 20.4345 LAYER M3  ;
    ANTENNAMAXSIDEAREACAR 0.203758 LAYER M3  ;
    ANTENNAPARTIALCUTAREA 0.08 LAYER V3  ;
    ANTENNAMAXCUTCAR 2.00866 LAYER V3  ;
    ANTENNADIFFAREA 2.014 LAYER M4  ;
    ANTENNAPARTIALMETALAREA 2.04 LAYER M4  ;
    ANTENNAPARTIALMETALSIDEAREA 0.0208 LAYER M4  ;
    ANTENNAGATEAREA 0.6552 LAYER M4  ;
    ANTENNAMAXAREACAR 23.5481 LAYER M4  ;
    ANTENNAMAXSIDEAREACAR 0.235504 LAYER M4  ;
    ANTENNAMAXCUTCAR 2.00866 LAYER V4  ;
    PORT
      LAYER M3 ;
        RECT 0.000000 87.520000 0.560000 87.680000 ;
    END
  END SRAM_in_B_addr[2]
  PIN SRAM_in_B_addr[1]
    DIRECTION OUTPUT ;
    USE SIGNAL ;
    ANTENNADIFFAREA 2.014 LAYER M3  ;
    ANTENNAPARTIALMETALAREA 4.3544 LAYER M3  ;
    ANTENNAPARTIALMETALSIDEAREA 0.04396 LAYER M3  ;
    ANTENNAMODEL OXIDE1 ;
    ANTENNAGATEAREA 0.6144 LAYER M3  ;
    ANTENNAMAXAREACAR 31.4396 LAYER M3  ;
    ANTENNAMAXSIDEAREACAR 0.321971 LAYER M3  ;
    ANTENNAMAXCUTCAR 1.66667 LAYER V3  ;
    PORT
      LAYER M3 ;
        RECT 0.000000 93.520000 0.560000 93.680000 ;
    END
  END SRAM_in_B_addr[1]
  PIN SRAM_in_B_addr[0]
    DIRECTION OUTPUT ;
    USE SIGNAL ;
    ANTENNADIFFAREA 3.488 LAYER M3  ;
    ANTENNAPARTIALMETALAREA 7.9144 LAYER M3  ;
    ANTENNAPARTIALMETALSIDEAREA 0.08076 LAYER M3  ;
    ANTENNAMODEL OXIDE1 ;
    ANTENNAGATEAREA 0.7512 LAYER M3  ;
    ANTENNAMAXAREACAR 36.9933 LAYER M3  ;
    ANTENNAMAXSIDEAREACAR 0.375538 LAYER M3  ;
    ANTENNAMAXCUTCAR 2.22222 LAYER V3  ;
    PORT
      LAYER M3 ;
        RECT 0.000000 99.520000 0.560000 99.680000 ;
    END
  END SRAM_in_B_addr[0]
  PIN SRAM_WENB1
    DIRECTION OUTPUT ;
    USE SIGNAL ;
    ANTENNADIFFAREA 1.76 LAYER M3  ;
    ANTENNAPARTIALMETALAREA 10.3144 LAYER M3  ;
    ANTENNAPARTIALMETALSIDEAREA 0.10316 LAYER M3  ;
    ANTENNAMODEL OXIDE1 ;
    ANTENNAGATEAREA 0.2232 LAYER M3  ;
    ANTENNAMAXAREACAR 54.4982 LAYER M3  ;
    ANTENNAMAXSIDEAREACAR 0.546953 LAYER M3  ;
    ANTENNAMAXCUTCAR 1.43369 LAYER V3  ;
    PORT
      LAYER M3 ;
        RECT 0.000000 39.520000 0.560000 39.680000 ;
    END
  END SRAM_WENB1
  PIN SRAM_WENB2
    DIRECTION OUTPUT ;
    USE SIGNAL ;
    ANTENNADIFFAREA 1.76 LAYER M3  ;
    ANTENNAPARTIALMETALAREA 5.8344 LAYER M3  ;
    ANTENNAPARTIALMETALSIDEAREA 0.05836 LAYER M3  ;
    PORT
      LAYER M3 ;
        RECT 0.000000 33.520000 0.560000 33.680000 ;
    END
  END SRAM_WENB2
  PIN SRAM_WENB3
    DIRECTION OUTPUT ;
    USE SIGNAL ;
    ANTENNADIFFAREA 1.76 LAYER M3  ;
    ANTENNAPARTIALMETALAREA 4.7944 LAYER M3  ;
    ANTENNAPARTIALMETALSIDEAREA 0.04796 LAYER M3  ;
    PORT
      LAYER M3 ;
        RECT 0.000000 27.520000 0.560000 27.680000 ;
    END
  END SRAM_WENB3
  PIN SRAM_WENB4
    DIRECTION OUTPUT ;
    USE SIGNAL ;
    ANTENNADIFFAREA 1.76 LAYER M3  ;
    ANTENNAPARTIALMETALAREA 7.3944 LAYER M3  ;
    ANTENNAPARTIALMETALSIDEAREA 0.07436 LAYER M3  ;
    ANTENNAMODEL OXIDE1 ;
    ANTENNAGATEAREA 0.1488 LAYER M3  ;
    ANTENNAMAXAREACAR 70.7776 LAYER M3  ;
    ANTENNAMAXSIDEAREACAR 0.712231 LAYER M3  ;
    ANTENNAMAXCUTCAR 1.07527 LAYER V3  ;
    PORT
      LAYER M3 ;
        RECT 0.000000 21.520000 0.560000 21.680000 ;
    END
  END SRAM_WENB4
  PIN VSS
    DIRECTION INOUT ;
    USE GROUND ;

# P/G power stripe data as pin
    PORT
      LAYER M4 ;
        RECT 56.000000 1.000000 58.000000 178.800000 ;
        RECT 26.000000 1.000000 28.000000 178.800000 ;
        RECT 1.000000 1.000000 3.000000 178.800000 ;
        RECT 116.000000 1.000000 118.000000 178.800000 ;
        RECT 86.000000 1.000000 88.000000 178.800000 ;
        RECT 146.000000 1.000000 148.000000 178.800000 ;
        RECT 176.000000 1.000000 178.000000 178.800000 ;
        RECT 206.000000 1.000000 208.000000 178.800000 ;
        RECT 237.000000 1.000000 239.000000 178.800000 ;
    END
# end of P/G power stripe data as pin

  END VSS
  PIN VDD
    DIRECTION INOUT ;
    USE POWER ;

# P/G power stripe data as pin
    PORT
      LAYER M4 ;
        RECT 52.000000 4.000000 54.000000 175.800000 ;
        RECT 22.000000 4.000000 24.000000 175.800000 ;
        RECT 4.000000 4.000000 6.000000 175.800000 ;
        RECT 112.000000 4.000000 114.000000 175.800000 ;
        RECT 82.000000 4.000000 84.000000 175.800000 ;
        RECT 142.000000 4.000000 144.000000 175.800000 ;
        RECT 172.000000 4.000000 174.000000 175.800000 ;
        RECT 202.000000 4.000000 204.000000 175.800000 ;
        RECT 234.000000 4.000000 236.000000 175.800000 ;
    END
# end of P/G power stripe data as pin

  END VDD
  OBS
    LAYER M1 ;
      RECT 0.000000 0.000000 240.000000 180.000000 ;
    LAYER M2 ;
      RECT 194.400000 177.520000 240.000000 180.000000 ;
      RECT 182.400000 177.520000 190.400000 180.000000 ;
      RECT 170.400000 177.520000 178.400000 180.000000 ;
      RECT 158.400000 177.520000 166.400000 180.000000 ;
      RECT 146.400000 177.520000 154.400000 180.000000 ;
      RECT 134.400000 177.520000 142.400000 180.000000 ;
      RECT 122.400000 177.520000 130.400000 180.000000 ;
      RECT 110.400000 177.520000 118.400000 180.000000 ;
      RECT 98.400000 177.520000 106.400000 180.000000 ;
      RECT 86.400000 177.520000 94.400000 180.000000 ;
      RECT 74.400000 177.520000 82.400000 180.000000 ;
      RECT 62.400000 177.520000 70.400000 180.000000 ;
      RECT 50.400000 177.520000 58.400000 180.000000 ;
      RECT 0.000000 177.520000 46.400000 180.000000 ;
      RECT 0.000000 2.520000 240.000000 177.520000 ;
      RECT 212.420000 0.000000 240.000000 2.520000 ;
      RECT 200.420000 0.000000 208.380000 2.520000 ;
      RECT 188.420000 0.000000 196.380000 2.520000 ;
      RECT 176.420000 0.000000 184.380000 2.520000 ;
      RECT 164.420000 0.000000 172.380000 2.520000 ;
      RECT 152.420000 0.000000 160.380000 2.520000 ;
      RECT 140.420000 0.000000 148.380000 2.520000 ;
      RECT 128.420000 0.000000 136.380000 2.520000 ;
      RECT 116.420000 0.000000 124.380000 2.520000 ;
      RECT 104.420000 0.000000 112.380000 2.520000 ;
      RECT 92.420000 0.000000 100.380000 2.520000 ;
      RECT 80.420000 0.000000 88.380000 2.520000 ;
      RECT 68.420000 0.000000 76.380000 2.520000 ;
      RECT 56.420000 0.000000 64.380000 2.520000 ;
      RECT 44.420000 0.000000 52.380000 2.520000 ;
      RECT 32.420000 0.000000 40.380000 2.520000 ;
      RECT 0.000000 0.000000 28.380000 2.520000 ;
    LAYER M3 ;
      RECT 0.000000 161.600000 240.000000 180.000000 ;
      RECT 2.480000 157.600000 240.000000 161.600000 ;
      RECT 0.000000 155.600000 240.000000 157.600000 ;
      RECT 2.480000 151.600000 240.000000 155.600000 ;
      RECT 0.000000 149.600000 240.000000 151.600000 ;
      RECT 2.480000 145.600000 240.000000 149.600000 ;
      RECT 0.000000 143.600000 240.000000 145.600000 ;
      RECT 2.480000 139.600000 240.000000 143.600000 ;
      RECT 0.000000 137.600000 240.000000 139.600000 ;
      RECT 2.480000 133.600000 240.000000 137.600000 ;
      RECT 0.000000 131.600000 240.000000 133.600000 ;
      RECT 2.480000 127.600000 240.000000 131.600000 ;
      RECT 0.000000 125.600000 240.000000 127.600000 ;
      RECT 2.480000 121.600000 240.000000 125.600000 ;
      RECT 0.000000 119.600000 240.000000 121.600000 ;
      RECT 2.480000 115.600000 240.000000 119.600000 ;
      RECT 0.000000 113.600000 240.000000 115.600000 ;
      RECT 2.480000 109.600000 240.000000 113.600000 ;
      RECT 0.000000 107.600000 240.000000 109.600000 ;
      RECT 2.480000 103.600000 240.000000 107.600000 ;
      RECT 0.000000 101.600000 240.000000 103.600000 ;
      RECT 2.480000 97.600000 240.000000 101.600000 ;
      RECT 0.000000 95.600000 240.000000 97.600000 ;
      RECT 2.480000 91.600000 240.000000 95.600000 ;
      RECT 0.000000 89.600000 240.000000 91.600000 ;
      RECT 2.480000 85.600000 240.000000 89.600000 ;
      RECT 0.000000 83.600000 240.000000 85.600000 ;
      RECT 2.480000 79.600000 240.000000 83.600000 ;
      RECT 0.000000 77.600000 240.000000 79.600000 ;
      RECT 2.480000 73.600000 240.000000 77.600000 ;
      RECT 0.000000 71.600000 240.000000 73.600000 ;
      RECT 2.480000 67.600000 240.000000 71.600000 ;
      RECT 0.000000 65.600000 240.000000 67.600000 ;
      RECT 2.480000 61.600000 240.000000 65.600000 ;
      RECT 0.000000 59.600000 240.000000 61.600000 ;
      RECT 2.480000 55.600000 240.000000 59.600000 ;
      RECT 0.000000 53.600000 240.000000 55.600000 ;
      RECT 2.480000 49.600000 240.000000 53.600000 ;
      RECT 0.000000 47.600000 240.000000 49.600000 ;
      RECT 2.480000 43.600000 240.000000 47.600000 ;
      RECT 0.000000 42.020000 240.000000 43.600000 ;
      RECT 0.000000 41.600000 237.480000 42.020000 ;
      RECT 2.480000 37.980000 237.480000 41.600000 ;
      RECT 2.480000 37.600000 240.000000 37.980000 ;
      RECT 0.000000 35.600000 240.000000 37.600000 ;
      RECT 2.480000 31.600000 240.000000 35.600000 ;
      RECT 0.000000 29.600000 240.000000 31.600000 ;
      RECT 2.480000 25.600000 240.000000 29.600000 ;
      RECT 0.000000 23.600000 240.000000 25.600000 ;
      RECT 2.480000 22.020000 240.000000 23.600000 ;
      RECT 2.480000 19.600000 237.480000 22.020000 ;
      RECT 0.000000 17.980000 237.480000 19.600000 ;
      RECT 0.000000 0.000000 240.000000 17.980000 ;
    LAYER M4 ;
      RECT 209.920000 177.720000 235.080000 180.000000 ;
      RECT 179.920000 177.720000 204.080000 180.000000 ;
      RECT 149.920000 177.720000 174.080000 180.000000 ;
      RECT 119.920000 177.720000 144.080000 180.000000 ;
      RECT 89.920000 177.720000 114.080000 180.000000 ;
      RECT 59.920000 177.720000 84.080000 180.000000 ;
      RECT 29.920000 177.720000 54.080000 180.000000 ;
      RECT 4.920000 177.720000 24.080000 180.000000 ;
      RECT 209.920000 2.080000 232.080000 177.720000 ;
      RECT 179.920000 2.080000 200.080000 177.720000 ;
      RECT 149.920000 2.080000 170.080000 177.720000 ;
      RECT 119.920000 2.080000 140.080000 177.720000 ;
      RECT 89.920000 2.080000 110.080000 177.720000 ;
      RECT 59.920000 2.080000 80.080000 177.720000 ;
      RECT 29.920000 2.080000 50.080000 177.720000 ;
      RECT 7.920000 2.080000 20.080000 177.720000 ;
      RECT 209.920000 0.000000 235.080000 2.080000 ;
      RECT 179.920000 0.000000 204.080000 2.080000 ;
      RECT 149.920000 0.000000 174.080000 2.080000 ;
      RECT 119.920000 0.000000 144.080000 2.080000 ;
      RECT 89.920000 0.000000 114.080000 2.080000 ;
      RECT 59.920000 0.000000 84.080000 2.080000 ;
      RECT 29.920000 0.000000 54.080000 2.080000 ;
      RECT 4.920000 0.000000 24.080000 2.080000 ;
  END
END Main_controller

END LIBRARY
